VERSION 5.8 ;
BUSBITCHARS "[]" ;
DIVIDERCHAR "/" ;
UNITS
    DATABASE MICRONS 1000 ;
END UNITS

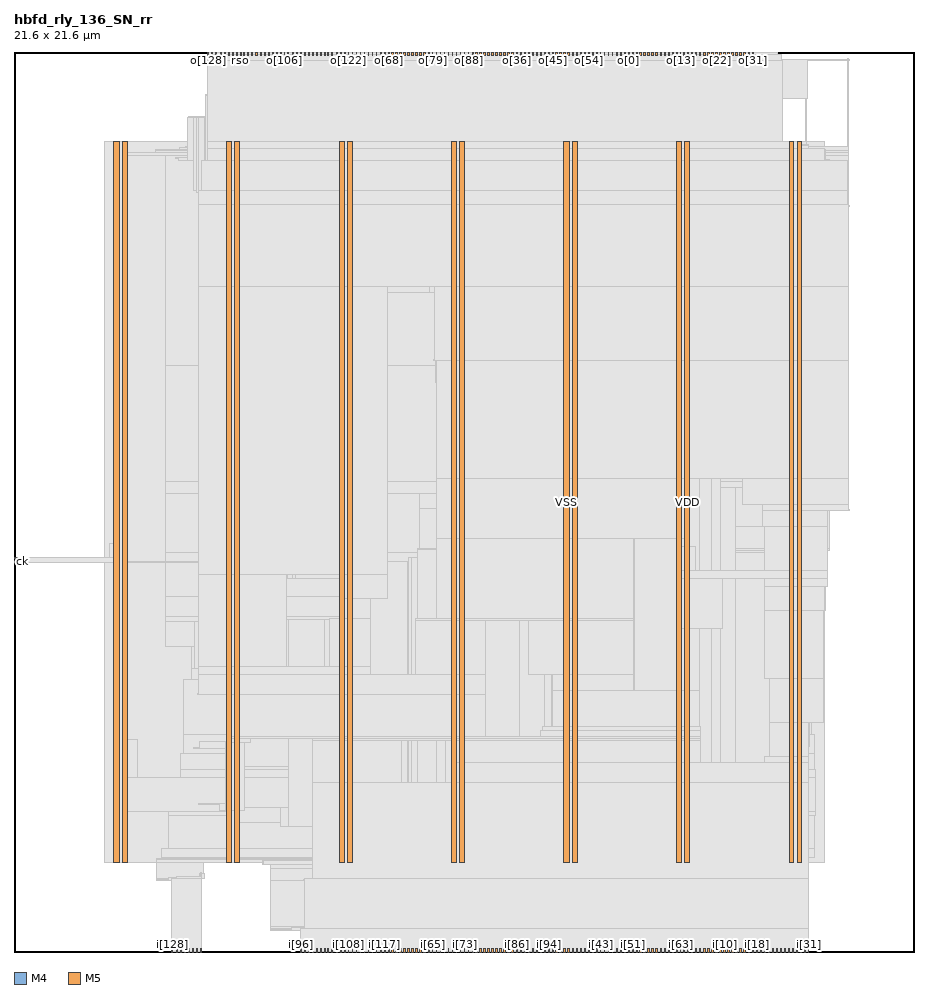
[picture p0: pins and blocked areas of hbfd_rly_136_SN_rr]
MACRO hbfd_rly_136_SN_rr
  FOREIGN hbfd_rly_136_SN_rr 0 0 ;
  CLASS BLOCK ;
  SIZE 21.6 BY 21.6 ;
  PIN ck
    DIRECTION INPUT ;
    USE SIGNAL ;
    PORT
      LAYER M4 ;
        RECT  0 9.36 0.084 9.384 ;
    END
  END ck
  PIN i[0]
    DIRECTION INPUT ;
    USE SIGNAL ;
    PORT
      LAYER M5 ;
        RECT  16.08 0 16.104 0.084 ;
    END
  END i[0]
  PIN i[100]
    DIRECTION INPUT ;
    USE SIGNAL ;
    PORT
      LAYER M5 ;
        RECT  7.248 0 7.272 0.084 ;
    END
  END i[100]
  PIN i[101]
    DIRECTION INPUT ;
    USE SIGNAL ;
    PORT
      LAYER M5 ;
        RECT  7.344 0 7.368 0.084 ;
    END
  END i[101]
  PIN i[102]
    DIRECTION INPUT ;
    USE SIGNAL ;
    PORT
      LAYER M5 ;
        RECT  7.44 0 7.464 0.084 ;
    END
  END i[102]
  PIN i[103]
    DIRECTION INPUT ;
    USE SIGNAL ;
    PORT
      LAYER M5 ;
        RECT  7.536 0 7.56 0.084 ;
    END
  END i[103]
  PIN i[104]
    DIRECTION INPUT ;
    USE SIGNAL ;
    PORT
      LAYER M5 ;
        RECT  7.632 0 7.656 0.084 ;
    END
  END i[104]
  PIN i[105]
    DIRECTION INPUT ;
    USE SIGNAL ;
    PORT
      LAYER M5 ;
        RECT  7.728 0 7.752 0.084 ;
    END
  END i[105]
  PIN i[106]
    DIRECTION INPUT ;
    USE SIGNAL ;
    PORT
      LAYER M5 ;
        RECT  7.824 0 7.848 0.084 ;
    END
  END i[106]
  PIN i[107]
    DIRECTION INPUT ;
    USE SIGNAL ;
    PORT
      LAYER M5 ;
        RECT  7.92 0 7.944 0.084 ;
    END
  END i[107]
  PIN i[108]
    DIRECTION INPUT ;
    USE SIGNAL ;
    PORT
      LAYER M5 ;
        RECT  8.016 0 8.04 0.084 ;
    END
  END i[108]
  PIN i[109]
    DIRECTION INPUT ;
    USE SIGNAL ;
    PORT
      LAYER M5 ;
        RECT  8.112 0 8.136 0.084 ;
    END
  END i[109]
  PIN i[10]
    DIRECTION INPUT ;
    USE SIGNAL ;
    PORT
      LAYER M5 ;
        RECT  17.04 0 17.064 0.084 ;
    END
  END i[10]
  PIN i[110]
    DIRECTION INPUT ;
    USE SIGNAL ;
    PORT
      LAYER M5 ;
        RECT  8.208 0 8.232 0.084 ;
    END
  END i[110]
  PIN i[111]
    DIRECTION INPUT ;
    USE SIGNAL ;
    PORT
      LAYER M5 ;
        RECT  8.304 0 8.328 0.084 ;
    END
  END i[111]
  PIN i[112]
    DIRECTION INPUT ;
    USE SIGNAL ;
    PORT
      LAYER M5 ;
        RECT  8.4 0 8.424 0.084 ;
    END
  END i[112]
  PIN i[113]
    DIRECTION INPUT ;
    USE SIGNAL ;
    PORT
      LAYER M5 ;
        RECT  8.496 0 8.52 0.084 ;
    END
  END i[113]
  PIN i[114]
    DIRECTION INPUT ;
    USE SIGNAL ;
    PORT
      LAYER M5 ;
        RECT  8.592 0 8.616 0.084 ;
    END
  END i[114]
  PIN i[115]
    DIRECTION INPUT ;
    USE SIGNAL ;
    PORT
      LAYER M5 ;
        RECT  8.688 0 8.712 0.084 ;
    END
  END i[115]
  PIN i[116]
    DIRECTION INPUT ;
    USE SIGNAL ;
    PORT
      LAYER M5 ;
        RECT  8.784 0 8.808 0.084 ;
    END
  END i[116]
  PIN i[117]
    DIRECTION INPUT ;
    USE SIGNAL ;
    PORT
      LAYER M5 ;
        RECT  8.88 0 8.904 0.084 ;
    END
  END i[117]
  PIN i[118]
    DIRECTION INPUT ;
    USE SIGNAL ;
    PORT
      LAYER M5 ;
        RECT  8.976 0 9 0.084 ;
    END
  END i[118]
  PIN i[119]
    DIRECTION INPUT ;
    USE SIGNAL ;
    PORT
      LAYER M5 ;
        RECT  9.072 0 9.096 0.084 ;
    END
  END i[119]
  PIN i[11]
    DIRECTION INPUT ;
    USE SIGNAL ;
    PORT
      LAYER M5 ;
        RECT  17.136 0 17.16 0.084 ;
    END
  END i[11]
  PIN i[120]
    DIRECTION INPUT ;
    USE SIGNAL ;
    PORT
      LAYER M5 ;
        RECT  9.168 0 9.192 0.084 ;
    END
  END i[120]
  PIN i[121]
    DIRECTION INPUT ;
    USE SIGNAL ;
    PORT
      LAYER M5 ;
        RECT  9.264 0 9.288 0.084 ;
    END
  END i[121]
  PIN i[122]
    DIRECTION INPUT ;
    USE SIGNAL ;
    PORT
      LAYER M5 ;
        RECT  9.36 0 9.384 0.084 ;
    END
  END i[122]
  PIN i[123]
    DIRECTION INPUT ;
    USE SIGNAL ;
    PORT
      LAYER M5 ;
        RECT  9.456 0 9.48 0.084 ;
    END
  END i[123]
  PIN i[124]
    DIRECTION INPUT ;
    USE SIGNAL ;
    PORT
      LAYER M5 ;
        RECT  9.552 0 9.576 0.084 ;
    END
  END i[124]
  PIN i[125]
    DIRECTION INPUT ;
    USE SIGNAL ;
    PORT
      LAYER M5 ;
        RECT  9.648 0 9.672 0.084 ;
    END
  END i[125]
  PIN i[126]
    DIRECTION INPUT ;
    USE SIGNAL ;
    PORT
      LAYER M5 ;
        RECT  9.744 0 9.768 0.084 ;
    END
  END i[126]
  PIN i[127]
    DIRECTION INPUT ;
    USE SIGNAL ;
    PORT
      LAYER M5 ;
        RECT  9.84 0 9.864 0.084 ;
    END
  END i[127]
  PIN i[128]
    DIRECTION INPUT ;
    USE SIGNAL ;
    PORT
      LAYER M5 ;
        RECT  3.792 0 3.816 0.084 ;
    END
  END i[128]
  PIN i[129]
    DIRECTION INPUT ;
    USE SIGNAL ;
    PORT
      LAYER M5 ;
        RECT  3.888 0 3.912 0.084 ;
    END
  END i[129]
  PIN i[12]
    DIRECTION INPUT ;
    USE SIGNAL ;
    PORT
      LAYER M5 ;
        RECT  17.232 0 17.256 0.084 ;
    END
  END i[12]
  PIN i[130]
    DIRECTION INPUT ;
    USE SIGNAL ;
    PORT
      LAYER M5 ;
        RECT  3.984 0 4.008 0.084 ;
    END
  END i[130]
  PIN i[131]
    DIRECTION INPUT ;
    USE SIGNAL ;
    PORT
      LAYER M5 ;
        RECT  4.08 0 4.104 0.084 ;
    END
  END i[131]
  PIN i[132]
    DIRECTION INPUT ;
    USE SIGNAL ;
    PORT
      LAYER M5 ;
        RECT  4.176 0 4.2 0.084 ;
    END
  END i[132]
  PIN i[133]
    DIRECTION INPUT ;
    USE SIGNAL ;
    PORT
      LAYER M5 ;
        RECT  4.272 0 4.296 0.084 ;
    END
  END i[133]
  PIN i[134]
    DIRECTION INPUT ;
    USE SIGNAL ;
    PORT
      LAYER M5 ;
        RECT  4.368 0 4.392 0.084 ;
    END
  END i[134]
  PIN i[135]
    DIRECTION INPUT ;
    USE SIGNAL ;
    PORT
      LAYER M5 ;
        RECT  4.464 0 4.488 0.084 ;
    END
  END i[135]
  PIN i[13]
    DIRECTION INPUT ;
    USE SIGNAL ;
    PORT
      LAYER M5 ;
        RECT  17.328 0 17.352 0.084 ;
    END
  END i[13]
  PIN i[14]
    DIRECTION INPUT ;
    USE SIGNAL ;
    PORT
      LAYER M5 ;
        RECT  17.424 0 17.448 0.084 ;
    END
  END i[14]
  PIN i[15]
    DIRECTION INPUT ;
    USE SIGNAL ;
    PORT
      LAYER M5 ;
        RECT  17.52 0 17.544 0.084 ;
    END
  END i[15]
  PIN i[16]
    DIRECTION INPUT ;
    USE SIGNAL ;
    PORT
      LAYER M5 ;
        RECT  17.616 0 17.64 0.084 ;
    END
  END i[16]
  PIN i[17]
    DIRECTION INPUT ;
    USE SIGNAL ;
    PORT
      LAYER M5 ;
        RECT  17.712 0 17.736 0.084 ;
    END
  END i[17]
  PIN i[18]
    DIRECTION INPUT ;
    USE SIGNAL ;
    PORT
      LAYER M5 ;
        RECT  17.808 0 17.832 0.084 ;
    END
  END i[18]
  PIN i[19]
    DIRECTION INPUT ;
    USE SIGNAL ;
    PORT
      LAYER M5 ;
        RECT  17.904 0 17.928 0.084 ;
    END
  END i[19]
  PIN i[1]
    DIRECTION INPUT ;
    USE SIGNAL ;
    PORT
      LAYER M5 ;
        RECT  16.176 0 16.2 0.084 ;
    END
  END i[1]
  PIN i[20]
    DIRECTION INPUT ;
    USE SIGNAL ;
    PORT
      LAYER M5 ;
        RECT  18 0 18.024 0.084 ;
    END
  END i[20]
  PIN i[21]
    DIRECTION INPUT ;
    USE SIGNAL ;
    PORT
      LAYER M5 ;
        RECT  18.096 0 18.12 0.084 ;
    END
  END i[21]
  PIN i[22]
    DIRECTION INPUT ;
    USE SIGNAL ;
    PORT
      LAYER M5 ;
        RECT  18.192 0 18.216 0.084 ;
    END
  END i[22]
  PIN i[23]
    DIRECTION INPUT ;
    USE SIGNAL ;
    PORT
      LAYER M5 ;
        RECT  18.288 0 18.312 0.084 ;
    END
  END i[23]
  PIN i[24]
    DIRECTION INPUT ;
    USE SIGNAL ;
    PORT
      LAYER M5 ;
        RECT  18.384 0 18.408 0.084 ;
    END
  END i[24]
  PIN i[25]
    DIRECTION INPUT ;
    USE SIGNAL ;
    PORT
      LAYER M5 ;
        RECT  18.48 0 18.504 0.084 ;
    END
  END i[25]
  PIN i[26]
    DIRECTION INPUT ;
    USE SIGNAL ;
    PORT
      LAYER M5 ;
        RECT  18.576 0 18.6 0.084 ;
    END
  END i[26]
  PIN i[27]
    DIRECTION INPUT ;
    USE SIGNAL ;
    PORT
      LAYER M5 ;
        RECT  18.672 0 18.696 0.084 ;
    END
  END i[27]
  PIN i[28]
    DIRECTION INPUT ;
    USE SIGNAL ;
    PORT
      LAYER M5 ;
        RECT  18.768 0 18.792 0.084 ;
    END
  END i[28]
  PIN i[29]
    DIRECTION INPUT ;
    USE SIGNAL ;
    PORT
      LAYER M5 ;
        RECT  18.864 0 18.888 0.084 ;
    END
  END i[29]
  PIN i[2]
    DIRECTION INPUT ;
    USE SIGNAL ;
    PORT
      LAYER M5 ;
        RECT  16.272 0 16.296 0.084 ;
    END
  END i[2]
  PIN i[30]
    DIRECTION INPUT ;
    USE SIGNAL ;
    PORT
      LAYER M5 ;
        RECT  18.96 0 18.984 0.084 ;
    END
  END i[30]
  PIN i[31]
    DIRECTION INPUT ;
    USE SIGNAL ;
    PORT
      LAYER M5 ;
        RECT  19.056 0 19.08 0.084 ;
    END
  END i[31]
  PIN i[32]
    DIRECTION INPUT ;
    USE SIGNAL ;
    PORT
      LAYER M5 ;
        RECT  13.008 0 13.032 0.084 ;
    END
  END i[32]
  PIN i[33]
    DIRECTION INPUT ;
    USE SIGNAL ;
    PORT
      LAYER M5 ;
        RECT  13.104 0 13.128 0.084 ;
    END
  END i[33]
  PIN i[34]
    DIRECTION INPUT ;
    USE SIGNAL ;
    PORT
      LAYER M5 ;
        RECT  13.2 0 13.224 0.084 ;
    END
  END i[34]
  PIN i[35]
    DIRECTION INPUT ;
    USE SIGNAL ;
    PORT
      LAYER M5 ;
        RECT  13.296 0 13.32 0.084 ;
    END
  END i[35]
  PIN i[36]
    DIRECTION INPUT ;
    USE SIGNAL ;
    PORT
      LAYER M5 ;
        RECT  13.392 0 13.416 0.084 ;
    END
  END i[36]
  PIN i[37]
    DIRECTION INPUT ;
    USE SIGNAL ;
    PORT
      LAYER M5 ;
        RECT  13.488 0 13.512 0.084 ;
    END
  END i[37]
  PIN i[38]
    DIRECTION INPUT ;
    USE SIGNAL ;
    PORT
      LAYER M5 ;
        RECT  13.584 0 13.608 0.084 ;
    END
  END i[38]
  PIN i[39]
    DIRECTION INPUT ;
    USE SIGNAL ;
    PORT
      LAYER M5 ;
        RECT  13.68 0 13.704 0.084 ;
    END
  END i[39]
  PIN i[3]
    DIRECTION INPUT ;
    USE SIGNAL ;
    PORT
      LAYER M5 ;
        RECT  16.368 0 16.392 0.084 ;
    END
  END i[3]
  PIN i[40]
    DIRECTION INPUT ;
    USE SIGNAL ;
    PORT
      LAYER M5 ;
        RECT  13.776 0 13.8 0.084 ;
    END
  END i[40]
  PIN i[41]
    DIRECTION INPUT ;
    USE SIGNAL ;
    PORT
      LAYER M5 ;
        RECT  13.872 0 13.896 0.084 ;
    END
  END i[41]
  PIN i[42]
    DIRECTION INPUT ;
    USE SIGNAL ;
    PORT
      LAYER M5 ;
        RECT  13.968 0 13.992 0.084 ;
    END
  END i[42]
  PIN i[43]
    DIRECTION INPUT ;
    USE SIGNAL ;
    PORT
      LAYER M5 ;
        RECT  14.064 0 14.088 0.084 ;
    END
  END i[43]
  PIN i[44]
    DIRECTION INPUT ;
    USE SIGNAL ;
    PORT
      LAYER M5 ;
        RECT  14.16 0 14.184 0.084 ;
    END
  END i[44]
  PIN i[45]
    DIRECTION INPUT ;
    USE SIGNAL ;
    PORT
      LAYER M5 ;
        RECT  14.256 0 14.28 0.084 ;
    END
  END i[45]
  PIN i[46]
    DIRECTION INPUT ;
    USE SIGNAL ;
    PORT
      LAYER M5 ;
        RECT  14.352 0 14.376 0.084 ;
    END
  END i[46]
  PIN i[47]
    DIRECTION INPUT ;
    USE SIGNAL ;
    PORT
      LAYER M5 ;
        RECT  14.448 0 14.472 0.084 ;
    END
  END i[47]
  PIN i[48]
    DIRECTION INPUT ;
    USE SIGNAL ;
    PORT
      LAYER M5 ;
        RECT  14.544 0 14.568 0.084 ;
    END
  END i[48]
  PIN i[49]
    DIRECTION INPUT ;
    USE SIGNAL ;
    PORT
      LAYER M5 ;
        RECT  14.64 0 14.664 0.084 ;
    END
  END i[49]
  PIN i[4]
    DIRECTION INPUT ;
    USE SIGNAL ;
    PORT
      LAYER M5 ;
        RECT  16.464 0 16.488 0.084 ;
    END
  END i[4]
  PIN i[50]
    DIRECTION INPUT ;
    USE SIGNAL ;
    PORT
      LAYER M5 ;
        RECT  14.736 0 14.76 0.084 ;
    END
  END i[50]
  PIN i[51]
    DIRECTION INPUT ;
    USE SIGNAL ;
    PORT
      LAYER M5 ;
        RECT  14.832 0 14.856 0.084 ;
    END
  END i[51]
  PIN i[52]
    DIRECTION INPUT ;
    USE SIGNAL ;
    PORT
      LAYER M5 ;
        RECT  14.928 0 14.952 0.084 ;
    END
  END i[52]
  PIN i[53]
    DIRECTION INPUT ;
    USE SIGNAL ;
    PORT
      LAYER M5 ;
        RECT  15.024 0 15.048 0.084 ;
    END
  END i[53]
  PIN i[54]
    DIRECTION INPUT ;
    USE SIGNAL ;
    PORT
      LAYER M5 ;
        RECT  15.12 0 15.144 0.084 ;
    END
  END i[54]
  PIN i[55]
    DIRECTION INPUT ;
    USE SIGNAL ;
    PORT
      LAYER M5 ;
        RECT  15.216 0 15.24 0.084 ;
    END
  END i[55]
  PIN i[56]
    DIRECTION INPUT ;
    USE SIGNAL ;
    PORT
      LAYER M5 ;
        RECT  15.312 0 15.336 0.084 ;
    END
  END i[56]
  PIN i[57]
    DIRECTION INPUT ;
    USE SIGNAL ;
    PORT
      LAYER M5 ;
        RECT  15.408 0 15.432 0.084 ;
    END
  END i[57]
  PIN i[58]
    DIRECTION INPUT ;
    USE SIGNAL ;
    PORT
      LAYER M5 ;
        RECT  15.504 0 15.528 0.084 ;
    END
  END i[58]
  PIN i[59]
    DIRECTION INPUT ;
    USE SIGNAL ;
    PORT
      LAYER M5 ;
        RECT  15.6 0 15.624 0.084 ;
    END
  END i[59]
  PIN i[5]
    DIRECTION INPUT ;
    USE SIGNAL ;
    PORT
      LAYER M5 ;
        RECT  16.56 0 16.584 0.084 ;
    END
  END i[5]
  PIN i[60]
    DIRECTION INPUT ;
    USE SIGNAL ;
    PORT
      LAYER M5 ;
        RECT  15.696 0 15.72 0.084 ;
    END
  END i[60]
  PIN i[61]
    DIRECTION INPUT ;
    USE SIGNAL ;
    PORT
      LAYER M5 ;
        RECT  15.792 0 15.816 0.084 ;
    END
  END i[61]
  PIN i[62]
    DIRECTION INPUT ;
    USE SIGNAL ;
    PORT
      LAYER M5 ;
        RECT  15.888 0 15.912 0.084 ;
    END
  END i[62]
  PIN i[63]
    DIRECTION INPUT ;
    USE SIGNAL ;
    PORT
      LAYER M5 ;
        RECT  15.984 0 16.008 0.084 ;
    END
  END i[63]
  PIN i[64]
    DIRECTION INPUT ;
    USE SIGNAL ;
    PORT
      LAYER M5 ;
        RECT  9.936 0 9.96 0.084 ;
    END
  END i[64]
  PIN i[65]
    DIRECTION INPUT ;
    USE SIGNAL ;
    PORT
      LAYER M5 ;
        RECT  10.032 0 10.056 0.084 ;
    END
  END i[65]
  PIN i[66]
    DIRECTION INPUT ;
    USE SIGNAL ;
    PORT
      LAYER M5 ;
        RECT  10.128 0 10.152 0.084 ;
    END
  END i[66]
  PIN i[67]
    DIRECTION INPUT ;
    USE SIGNAL ;
    PORT
      LAYER M5 ;
        RECT  10.224 0 10.248 0.084 ;
    END
  END i[67]
  PIN i[68]
    DIRECTION INPUT ;
    USE SIGNAL ;
    PORT
      LAYER M5 ;
        RECT  10.32 0 10.344 0.084 ;
    END
  END i[68]
  PIN i[69]
    DIRECTION INPUT ;
    USE SIGNAL ;
    PORT
      LAYER M5 ;
        RECT  10.416 0 10.44 0.084 ;
    END
  END i[69]
  PIN i[6]
    DIRECTION INPUT ;
    USE SIGNAL ;
    PORT
      LAYER M5 ;
        RECT  16.656 0 16.68 0.084 ;
    END
  END i[6]
  PIN i[70]
    DIRECTION INPUT ;
    USE SIGNAL ;
    PORT
      LAYER M5 ;
        RECT  10.512 0 10.536 0.084 ;
    END
  END i[70]
  PIN i[71]
    DIRECTION INPUT ;
    USE SIGNAL ;
    PORT
      LAYER M5 ;
        RECT  10.608 0 10.632 0.084 ;
    END
  END i[71]
  PIN i[72]
    DIRECTION INPUT ;
    USE SIGNAL ;
    PORT
      LAYER M5 ;
        RECT  10.704 0 10.728 0.084 ;
    END
  END i[72]
  PIN i[73]
    DIRECTION INPUT ;
    USE SIGNAL ;
    PORT
      LAYER M5 ;
        RECT  10.8 0 10.824 0.084 ;
    END
  END i[73]
  PIN i[74]
    DIRECTION INPUT ;
    USE SIGNAL ;
    PORT
      LAYER M5 ;
        RECT  10.896 0 10.92 0.084 ;
    END
  END i[74]
  PIN i[75]
    DIRECTION INPUT ;
    USE SIGNAL ;
    PORT
      LAYER M5 ;
        RECT  10.992 0 11.016 0.084 ;
    END
  END i[75]
  PIN i[76]
    DIRECTION INPUT ;
    USE SIGNAL ;
    PORT
      LAYER M5 ;
        RECT  11.088 0 11.112 0.084 ;
    END
  END i[76]
  PIN i[77]
    DIRECTION INPUT ;
    USE SIGNAL ;
    PORT
      LAYER M5 ;
        RECT  11.184 0 11.208 0.084 ;
    END
  END i[77]
  PIN i[78]
    DIRECTION INPUT ;
    USE SIGNAL ;
    PORT
      LAYER M5 ;
        RECT  11.28 0 11.304 0.084 ;
    END
  END i[78]
  PIN i[79]
    DIRECTION INPUT ;
    USE SIGNAL ;
    PORT
      LAYER M5 ;
        RECT  11.376 0 11.4 0.084 ;
    END
  END i[79]
  PIN i[7]
    DIRECTION INPUT ;
    USE SIGNAL ;
    PORT
      LAYER M5 ;
        RECT  16.752 0 16.776 0.084 ;
    END
  END i[7]
  PIN i[80]
    DIRECTION INPUT ;
    USE SIGNAL ;
    PORT
      LAYER M5 ;
        RECT  11.472 0 11.496 0.084 ;
    END
  END i[80]
  PIN i[81]
    DIRECTION INPUT ;
    USE SIGNAL ;
    PORT
      LAYER M5 ;
        RECT  11.568 0 11.592 0.084 ;
    END
  END i[81]
  PIN i[82]
    DIRECTION INPUT ;
    USE SIGNAL ;
    PORT
      LAYER M5 ;
        RECT  11.664 0 11.688 0.084 ;
    END
  END i[82]
  PIN i[83]
    DIRECTION INPUT ;
    USE SIGNAL ;
    PORT
      LAYER M5 ;
        RECT  11.76 0 11.784 0.084 ;
    END
  END i[83]
  PIN i[84]
    DIRECTION INPUT ;
    USE SIGNAL ;
    PORT
      LAYER M5 ;
        RECT  11.856 0 11.88 0.084 ;
    END
  END i[84]
  PIN i[85]
    DIRECTION INPUT ;
    USE SIGNAL ;
    PORT
      LAYER M5 ;
        RECT  11.952 0 11.976 0.084 ;
    END
  END i[85]
  PIN i[86]
    DIRECTION INPUT ;
    USE SIGNAL ;
    PORT
      LAYER M5 ;
        RECT  12.048 0 12.072 0.084 ;
    END
  END i[86]
  PIN i[87]
    DIRECTION INPUT ;
    USE SIGNAL ;
    PORT
      LAYER M5 ;
        RECT  12.144 0 12.168 0.084 ;
    END
  END i[87]
  PIN i[88]
    DIRECTION INPUT ;
    USE SIGNAL ;
    PORT
      LAYER M5 ;
        RECT  12.24 0 12.264 0.084 ;
    END
  END i[88]
  PIN i[89]
    DIRECTION INPUT ;
    USE SIGNAL ;
    PORT
      LAYER M5 ;
        RECT  12.336 0 12.36 0.084 ;
    END
  END i[89]
  PIN i[8]
    DIRECTION INPUT ;
    USE SIGNAL ;
    PORT
      LAYER M5 ;
        RECT  16.848 0 16.872 0.084 ;
    END
  END i[8]
  PIN i[90]
    DIRECTION INPUT ;
    USE SIGNAL ;
    PORT
      LAYER M5 ;
        RECT  12.432 0 12.456 0.084 ;
    END
  END i[90]
  PIN i[91]
    DIRECTION INPUT ;
    USE SIGNAL ;
    PORT
      LAYER M5 ;
        RECT  12.528 0 12.552 0.084 ;
    END
  END i[91]
  PIN i[92]
    DIRECTION INPUT ;
    USE SIGNAL ;
    PORT
      LAYER M5 ;
        RECT  12.624 0 12.648 0.084 ;
    END
  END i[92]
  PIN i[93]
    DIRECTION INPUT ;
    USE SIGNAL ;
    PORT
      LAYER M5 ;
        RECT  12.72 0 12.744 0.084 ;
    END
  END i[93]
  PIN i[94]
    DIRECTION INPUT ;
    USE SIGNAL ;
    PORT
      LAYER M5 ;
        RECT  12.816 0 12.84 0.084 ;
    END
  END i[94]
  PIN i[95]
    DIRECTION INPUT ;
    USE SIGNAL ;
    PORT
      LAYER M5 ;
        RECT  12.912 0 12.936 0.084 ;
    END
  END i[95]
  PIN i[96]
    DIRECTION INPUT ;
    USE SIGNAL ;
    PORT
      LAYER M5 ;
        RECT  6.864 0 6.888 0.084 ;
    END
  END i[96]
  PIN i[97]
    DIRECTION INPUT ;
    USE SIGNAL ;
    PORT
      LAYER M5 ;
        RECT  6.96 0 6.984 0.084 ;
    END
  END i[97]
  PIN i[98]
    DIRECTION INPUT ;
    USE SIGNAL ;
    PORT
      LAYER M5 ;
        RECT  7.056 0 7.08 0.084 ;
    END
  END i[98]
  PIN i[99]
    DIRECTION INPUT ;
    USE SIGNAL ;
    PORT
      LAYER M5 ;
        RECT  7.152 0 7.176 0.084 ;
    END
  END i[99]
  PIN i[9]
    DIRECTION INPUT ;
    USE SIGNAL ;
    PORT
      LAYER M5 ;
        RECT  16.944 0 16.968 0.084 ;
    END
  END i[9]
  PIN o[0]
    DIRECTION OUTPUT ;
    USE SIGNAL ;
    PORT
      LAYER M5 ;
        RECT  14.736 21.516 14.76 21.6 ;
    END
  END o[0]
  PIN o[100]
    DIRECTION OUTPUT ;
    USE SIGNAL ;
    PORT
      LAYER M5 ;
        RECT  5.904 21.516 5.928 21.6 ;
    END
  END o[100]
  PIN o[101]
    DIRECTION OUTPUT ;
    USE SIGNAL ;
    PORT
      LAYER M5 ;
        RECT  6 21.516 6.024 21.6 ;
    END
  END o[101]
  PIN o[102]
    DIRECTION OUTPUT ;
    USE SIGNAL ;
    PORT
      LAYER M5 ;
        RECT  6.096 21.516 6.12 21.6 ;
    END
  END o[102]
  PIN o[103]
    DIRECTION OUTPUT ;
    USE SIGNAL ;
    PORT
      LAYER M5 ;
        RECT  6.192 21.516 6.216 21.6 ;
    END
  END o[103]
  PIN o[104]
    DIRECTION OUTPUT ;
    USE SIGNAL ;
    PORT
      LAYER M5 ;
        RECT  6.288 21.516 6.312 21.6 ;
    END
  END o[104]
  PIN o[105]
    DIRECTION OUTPUT ;
    USE SIGNAL ;
    PORT
      LAYER M5 ;
        RECT  6.384 21.516 6.408 21.6 ;
    END
  END o[105]
  PIN o[106]
    DIRECTION OUTPUT ;
    USE SIGNAL ;
    PORT
      LAYER M5 ;
        RECT  6.48 21.516 6.504 21.6 ;
    END
  END o[106]
  PIN o[107]
    DIRECTION OUTPUT ;
    USE SIGNAL ;
    PORT
      LAYER M5 ;
        RECT  6.576 21.516 6.6 21.6 ;
    END
  END o[107]
  PIN o[108]
    DIRECTION OUTPUT ;
    USE SIGNAL ;
    PORT
      LAYER M5 ;
        RECT  6.672 21.516 6.696 21.6 ;
    END
  END o[108]
  PIN o[109]
    DIRECTION OUTPUT ;
    USE SIGNAL ;
    PORT
      LAYER M5 ;
        RECT  6.768 21.516 6.792 21.6 ;
    END
  END o[109]
  PIN o[10]
    DIRECTION OUTPUT ;
    USE SIGNAL ;
    PORT
      LAYER M5 ;
        RECT  15.696 21.516 15.72 21.6 ;
    END
  END o[10]
  PIN o[110]
    DIRECTION OUTPUT ;
    USE SIGNAL ;
    PORT
      LAYER M5 ;
        RECT  6.864 21.516 6.888 21.6 ;
    END
  END o[110]
  PIN o[111]
    DIRECTION OUTPUT ;
    USE SIGNAL ;
    PORT
      LAYER M5 ;
        RECT  6.96 21.516 6.984 21.6 ;
    END
  END o[111]
  PIN o[112]
    DIRECTION OUTPUT ;
    USE SIGNAL ;
    PORT
      LAYER M5 ;
        RECT  7.056 21.516 7.08 21.6 ;
    END
  END o[112]
  PIN o[113]
    DIRECTION OUTPUT ;
    USE SIGNAL ;
    PORT
      LAYER M5 ;
        RECT  7.152 21.516 7.176 21.6 ;
    END
  END o[113]
  PIN o[114]
    DIRECTION OUTPUT ;
    USE SIGNAL ;
    PORT
      LAYER M5 ;
        RECT  7.248 21.516 7.272 21.6 ;
    END
  END o[114]
  PIN o[115]
    DIRECTION OUTPUT ;
    USE SIGNAL ;
    PORT
      LAYER M5 ;
        RECT  7.344 21.516 7.368 21.6 ;
    END
  END o[115]
  PIN o[116]
    DIRECTION OUTPUT ;
    USE SIGNAL ;
    PORT
      LAYER M5 ;
        RECT  7.44 21.516 7.464 21.6 ;
    END
  END o[116]
  PIN o[117]
    DIRECTION OUTPUT ;
    USE SIGNAL ;
    PORT
      LAYER M5 ;
        RECT  7.536 21.516 7.56 21.6 ;
    END
  END o[117]
  PIN o[118]
    DIRECTION OUTPUT ;
    USE SIGNAL ;
    PORT
      LAYER M5 ;
        RECT  7.632 21.516 7.656 21.6 ;
    END
  END o[118]
  PIN o[119]
    DIRECTION OUTPUT ;
    USE SIGNAL ;
    PORT
      LAYER M5 ;
        RECT  7.728 21.516 7.752 21.6 ;
    END
  END o[119]
  PIN o[11]
    DIRECTION OUTPUT ;
    USE SIGNAL ;
    PORT
      LAYER M5 ;
        RECT  15.792 21.516 15.816 21.6 ;
    END
  END o[11]
  PIN o[120]
    DIRECTION OUTPUT ;
    USE SIGNAL ;
    PORT
      LAYER M5 ;
        RECT  7.824 21.516 7.848 21.6 ;
    END
  END o[120]
  PIN o[121]
    DIRECTION OUTPUT ;
    USE SIGNAL ;
    PORT
      LAYER M5 ;
        RECT  7.92 21.516 7.944 21.6 ;
    END
  END o[121]
  PIN o[122]
    DIRECTION OUTPUT ;
    USE SIGNAL ;
    PORT
      LAYER M5 ;
        RECT  8.016 21.516 8.04 21.6 ;
    END
  END o[122]
  PIN o[123]
    DIRECTION OUTPUT ;
    USE SIGNAL ;
    PORT
      LAYER M5 ;
        RECT  8.112 21.516 8.136 21.6 ;
    END
  END o[123]
  PIN o[124]
    DIRECTION OUTPUT ;
    USE SIGNAL ;
    PORT
      LAYER M5 ;
        RECT  8.208 21.516 8.232 21.6 ;
    END
  END o[124]
  PIN o[125]
    DIRECTION OUTPUT ;
    USE SIGNAL ;
    PORT
      LAYER M5 ;
        RECT  8.304 21.516 8.328 21.6 ;
    END
  END o[125]
  PIN o[126]
    DIRECTION OUTPUT ;
    USE SIGNAL ;
    PORT
      LAYER M5 ;
        RECT  8.4 21.516 8.424 21.6 ;
    END
  END o[126]
  PIN o[127]
    DIRECTION OUTPUT ;
    USE SIGNAL ;
    PORT
      LAYER M5 ;
        RECT  8.496 21.516 8.52 21.6 ;
    END
  END o[127]
  PIN o[128]
    DIRECTION OUTPUT ;
    USE SIGNAL ;
    PORT
      LAYER M5 ;
        RECT  4.656 21.516 4.68 21.6 ;
    END
  END o[128]
  PIN o[129]
    DIRECTION OUTPUT ;
    USE SIGNAL ;
    PORT
      LAYER M5 ;
        RECT  4.752 21.516 4.776 21.6 ;
    END
  END o[129]
  PIN o[12]
    DIRECTION OUTPUT ;
    USE SIGNAL ;
    PORT
      LAYER M5 ;
        RECT  15.888 21.516 15.912 21.6 ;
    END
  END o[12]
  PIN o[130]
    DIRECTION OUTPUT ;
    USE SIGNAL ;
    PORT
      LAYER M5 ;
        RECT  4.848 21.516 4.872 21.6 ;
    END
  END o[130]
  PIN o[131]
    DIRECTION OUTPUT ;
    USE SIGNAL ;
    PORT
      LAYER M5 ;
        RECT  4.944 21.516 4.968 21.6 ;
    END
  END o[131]
  PIN o[132]
    DIRECTION OUTPUT ;
    USE SIGNAL ;
    PORT
      LAYER M5 ;
        RECT  5.04 21.516 5.064 21.6 ;
    END
  END o[132]
  PIN o[133]
    DIRECTION OUTPUT ;
    USE SIGNAL ;
    PORT
      LAYER M5 ;
        RECT  5.136 21.516 5.16 21.6 ;
    END
  END o[133]
  PIN o[134]
    DIRECTION OUTPUT ;
    USE SIGNAL ;
    PORT
      LAYER M5 ;
        RECT  5.232 21.516 5.256 21.6 ;
    END
  END o[134]
  PIN o[135]
    DIRECTION OUTPUT ;
    USE SIGNAL ;
    PORT
      LAYER M5 ;
        RECT  5.328 21.516 5.352 21.6 ;
    END
  END o[135]
  PIN o[13]
    DIRECTION OUTPUT ;
    USE SIGNAL ;
    PORT
      LAYER M5 ;
        RECT  15.984 21.516 16.008 21.6 ;
    END
  END o[13]
  PIN o[14]
    DIRECTION OUTPUT ;
    USE SIGNAL ;
    PORT
      LAYER M5 ;
        RECT  16.08 21.516 16.104 21.6 ;
    END
  END o[14]
  PIN o[15]
    DIRECTION OUTPUT ;
    USE SIGNAL ;
    PORT
      LAYER M5 ;
        RECT  16.176 21.516 16.2 21.6 ;
    END
  END o[15]
  PIN o[16]
    DIRECTION OUTPUT ;
    USE SIGNAL ;
    PORT
      LAYER M5 ;
        RECT  16.272 21.516 16.296 21.6 ;
    END
  END o[16]
  PIN o[17]
    DIRECTION OUTPUT ;
    USE SIGNAL ;
    PORT
      LAYER M5 ;
        RECT  16.368 21.516 16.392 21.6 ;
    END
  END o[17]
  PIN o[18]
    DIRECTION OUTPUT ;
    USE SIGNAL ;
    PORT
      LAYER M5 ;
        RECT  16.464 21.516 16.488 21.6 ;
    END
  END o[18]
  PIN o[19]
    DIRECTION OUTPUT ;
    USE SIGNAL ;
    PORT
      LAYER M5 ;
        RECT  16.56 21.516 16.584 21.6 ;
    END
  END o[19]
  PIN o[1]
    DIRECTION OUTPUT ;
    USE SIGNAL ;
    PORT
      LAYER M5 ;
        RECT  14.832 21.516 14.856 21.6 ;
    END
  END o[1]
  PIN o[20]
    DIRECTION OUTPUT ;
    USE SIGNAL ;
    PORT
      LAYER M5 ;
        RECT  16.656 21.516 16.68 21.6 ;
    END
  END o[20]
  PIN o[21]
    DIRECTION OUTPUT ;
    USE SIGNAL ;
    PORT
      LAYER M5 ;
        RECT  16.752 21.516 16.776 21.6 ;
    END
  END o[21]
  PIN o[22]
    DIRECTION OUTPUT ;
    USE SIGNAL ;
    PORT
      LAYER M5 ;
        RECT  16.848 21.516 16.872 21.6 ;
    END
  END o[22]
  PIN o[23]
    DIRECTION OUTPUT ;
    USE SIGNAL ;
    PORT
      LAYER M5 ;
        RECT  16.944 21.516 16.968 21.6 ;
    END
  END o[23]
  PIN o[24]
    DIRECTION OUTPUT ;
    USE SIGNAL ;
    PORT
      LAYER M5 ;
        RECT  17.04 21.516 17.064 21.6 ;
    END
  END o[24]
  PIN o[25]
    DIRECTION OUTPUT ;
    USE SIGNAL ;
    PORT
      LAYER M5 ;
        RECT  17.136 21.516 17.16 21.6 ;
    END
  END o[25]
  PIN o[26]
    DIRECTION OUTPUT ;
    USE SIGNAL ;
    PORT
      LAYER M5 ;
        RECT  17.232 21.516 17.256 21.6 ;
    END
  END o[26]
  PIN o[27]
    DIRECTION OUTPUT ;
    USE SIGNAL ;
    PORT
      LAYER M5 ;
        RECT  17.328 21.516 17.352 21.6 ;
    END
  END o[27]
  PIN o[28]
    DIRECTION OUTPUT ;
    USE SIGNAL ;
    PORT
      LAYER M5 ;
        RECT  17.424 21.516 17.448 21.6 ;
    END
  END o[28]
  PIN o[29]
    DIRECTION OUTPUT ;
    USE SIGNAL ;
    PORT
      LAYER M5 ;
        RECT  17.52 21.516 17.544 21.6 ;
    END
  END o[29]
  PIN o[2]
    DIRECTION OUTPUT ;
    USE SIGNAL ;
    PORT
      LAYER M5 ;
        RECT  14.928 21.516 14.952 21.6 ;
    END
  END o[2]
  PIN o[30]
    DIRECTION OUTPUT ;
    USE SIGNAL ;
    PORT
      LAYER M5 ;
        RECT  17.616 21.516 17.64 21.6 ;
    END
  END o[30]
  PIN o[31]
    DIRECTION OUTPUT ;
    USE SIGNAL ;
    PORT
      LAYER M5 ;
        RECT  17.712 21.516 17.736 21.6 ;
    END
  END o[31]
  PIN o[32]
    DIRECTION OUTPUT ;
    USE SIGNAL ;
    PORT
      LAYER M5 ;
        RECT  11.664 21.516 11.688 21.6 ;
    END
  END o[32]
  PIN o[33]
    DIRECTION OUTPUT ;
    USE SIGNAL ;
    PORT
      LAYER M5 ;
        RECT  11.76 21.516 11.784 21.6 ;
    END
  END o[33]
  PIN o[34]
    DIRECTION OUTPUT ;
    USE SIGNAL ;
    PORT
      LAYER M5 ;
        RECT  11.856 21.516 11.88 21.6 ;
    END
  END o[34]
  PIN o[35]
    DIRECTION OUTPUT ;
    USE SIGNAL ;
    PORT
      LAYER M5 ;
        RECT  11.952 21.516 11.976 21.6 ;
    END
  END o[35]
  PIN o[36]
    DIRECTION OUTPUT ;
    USE SIGNAL ;
    PORT
      LAYER M5 ;
        RECT  12.048 21.516 12.072 21.6 ;
    END
  END o[36]
  PIN o[37]
    DIRECTION OUTPUT ;
    USE SIGNAL ;
    PORT
      LAYER M5 ;
        RECT  12.144 21.516 12.168 21.6 ;
    END
  END o[37]
  PIN o[38]
    DIRECTION OUTPUT ;
    USE SIGNAL ;
    PORT
      LAYER M5 ;
        RECT  12.24 21.516 12.264 21.6 ;
    END
  END o[38]
  PIN o[39]
    DIRECTION OUTPUT ;
    USE SIGNAL ;
    PORT
      LAYER M5 ;
        RECT  12.336 21.516 12.36 21.6 ;
    END
  END o[39]
  PIN o[3]
    DIRECTION OUTPUT ;
    USE SIGNAL ;
    PORT
      LAYER M5 ;
        RECT  15.024 21.516 15.048 21.6 ;
    END
  END o[3]
  PIN o[40]
    DIRECTION OUTPUT ;
    USE SIGNAL ;
    PORT
      LAYER M5 ;
        RECT  12.432 21.516 12.456 21.6 ;
    END
  END o[40]
  PIN o[41]
    DIRECTION OUTPUT ;
    USE SIGNAL ;
    PORT
      LAYER M5 ;
        RECT  12.528 21.516 12.552 21.6 ;
    END
  END o[41]
  PIN o[42]
    DIRECTION OUTPUT ;
    USE SIGNAL ;
    PORT
      LAYER M5 ;
        RECT  12.624 21.516 12.648 21.6 ;
    END
  END o[42]
  PIN o[43]
    DIRECTION OUTPUT ;
    USE SIGNAL ;
    PORT
      LAYER M5 ;
        RECT  12.72 21.516 12.744 21.6 ;
    END
  END o[43]
  PIN o[44]
    DIRECTION OUTPUT ;
    USE SIGNAL ;
    PORT
      LAYER M5 ;
        RECT  12.816 21.516 12.84 21.6 ;
    END
  END o[44]
  PIN o[45]
    DIRECTION OUTPUT ;
    USE SIGNAL ;
    PORT
      LAYER M5 ;
        RECT  12.912 21.516 12.936 21.6 ;
    END
  END o[45]
  PIN o[46]
    DIRECTION OUTPUT ;
    USE SIGNAL ;
    PORT
      LAYER M5 ;
        RECT  13.008 21.516 13.032 21.6 ;
    END
  END o[46]
  PIN o[47]
    DIRECTION OUTPUT ;
    USE SIGNAL ;
    PORT
      LAYER M5 ;
        RECT  13.104 21.516 13.128 21.6 ;
    END
  END o[47]
  PIN o[48]
    DIRECTION OUTPUT ;
    USE SIGNAL ;
    PORT
      LAYER M5 ;
        RECT  13.2 21.516 13.224 21.6 ;
    END
  END o[48]
  PIN o[49]
    DIRECTION OUTPUT ;
    USE SIGNAL ;
    PORT
      LAYER M5 ;
        RECT  13.296 21.516 13.32 21.6 ;
    END
  END o[49]
  PIN o[4]
    DIRECTION OUTPUT ;
    USE SIGNAL ;
    PORT
      LAYER M5 ;
        RECT  15.12 21.516 15.144 21.6 ;
    END
  END o[4]
  PIN o[50]
    DIRECTION OUTPUT ;
    USE SIGNAL ;
    PORT
      LAYER M5 ;
        RECT  13.392 21.516 13.416 21.6 ;
    END
  END o[50]
  PIN o[51]
    DIRECTION OUTPUT ;
    USE SIGNAL ;
    PORT
      LAYER M5 ;
        RECT  13.488 21.516 13.512 21.6 ;
    END
  END o[51]
  PIN o[52]
    DIRECTION OUTPUT ;
    USE SIGNAL ;
    PORT
      LAYER M5 ;
        RECT  13.584 21.516 13.608 21.6 ;
    END
  END o[52]
  PIN o[53]
    DIRECTION OUTPUT ;
    USE SIGNAL ;
    PORT
      LAYER M5 ;
        RECT  13.68 21.516 13.704 21.6 ;
    END
  END o[53]
  PIN o[54]
    DIRECTION OUTPUT ;
    USE SIGNAL ;
    PORT
      LAYER M5 ;
        RECT  13.776 21.516 13.8 21.6 ;
    END
  END o[54]
  PIN o[55]
    DIRECTION OUTPUT ;
    USE SIGNAL ;
    PORT
      LAYER M5 ;
        RECT  13.872 21.516 13.896 21.6 ;
    END
  END o[55]
  PIN o[56]
    DIRECTION OUTPUT ;
    USE SIGNAL ;
    PORT
      LAYER M5 ;
        RECT  13.968 21.516 13.992 21.6 ;
    END
  END o[56]
  PIN o[57]
    DIRECTION OUTPUT ;
    USE SIGNAL ;
    PORT
      LAYER M5 ;
        RECT  14.064 21.516 14.088 21.6 ;
    END
  END o[57]
  PIN o[58]
    DIRECTION OUTPUT ;
    USE SIGNAL ;
    PORT
      LAYER M5 ;
        RECT  14.16 21.516 14.184 21.6 ;
    END
  END o[58]
  PIN o[59]
    DIRECTION OUTPUT ;
    USE SIGNAL ;
    PORT
      LAYER M5 ;
        RECT  14.256 21.516 14.28 21.6 ;
    END
  END o[59]
  PIN o[5]
    DIRECTION OUTPUT ;
    USE SIGNAL ;
    PORT
      LAYER M5 ;
        RECT  15.216 21.516 15.24 21.6 ;
    END
  END o[5]
  PIN o[60]
    DIRECTION OUTPUT ;
    USE SIGNAL ;
    PORT
      LAYER M5 ;
        RECT  14.352 21.516 14.376 21.6 ;
    END
  END o[60]
  PIN o[61]
    DIRECTION OUTPUT ;
    USE SIGNAL ;
    PORT
      LAYER M5 ;
        RECT  14.448 21.516 14.472 21.6 ;
    END
  END o[61]
  PIN o[62]
    DIRECTION OUTPUT ;
    USE SIGNAL ;
    PORT
      LAYER M5 ;
        RECT  14.544 21.516 14.568 21.6 ;
    END
  END o[62]
  PIN o[63]
    DIRECTION OUTPUT ;
    USE SIGNAL ;
    PORT
      LAYER M5 ;
        RECT  14.64 21.516 14.664 21.6 ;
    END
  END o[63]
  PIN o[64]
    DIRECTION OUTPUT ;
    USE SIGNAL ;
    PORT
      LAYER M5 ;
        RECT  8.592 21.516 8.616 21.6 ;
    END
  END o[64]
  PIN o[65]
    DIRECTION OUTPUT ;
    USE SIGNAL ;
    PORT
      LAYER M5 ;
        RECT  8.688 21.516 8.712 21.6 ;
    END
  END o[65]
  PIN o[66]
    DIRECTION OUTPUT ;
    USE SIGNAL ;
    PORT
      LAYER M5 ;
        RECT  8.784 21.516 8.808 21.6 ;
    END
  END o[66]
  PIN o[67]
    DIRECTION OUTPUT ;
    USE SIGNAL ;
    PORT
      LAYER M5 ;
        RECT  8.88 21.516 8.904 21.6 ;
    END
  END o[67]
  PIN o[68]
    DIRECTION OUTPUT ;
    USE SIGNAL ;
    PORT
      LAYER M5 ;
        RECT  8.976 21.516 9 21.6 ;
    END
  END o[68]
  PIN o[69]
    DIRECTION OUTPUT ;
    USE SIGNAL ;
    PORT
      LAYER M5 ;
        RECT  9.072 21.516 9.096 21.6 ;
    END
  END o[69]
  PIN o[6]
    DIRECTION OUTPUT ;
    USE SIGNAL ;
    PORT
      LAYER M5 ;
        RECT  15.312 21.516 15.336 21.6 ;
    END
  END o[6]
  PIN o[70]
    DIRECTION OUTPUT ;
    USE SIGNAL ;
    PORT
      LAYER M5 ;
        RECT  9.168 21.516 9.192 21.6 ;
    END
  END o[70]
  PIN o[71]
    DIRECTION OUTPUT ;
    USE SIGNAL ;
    PORT
      LAYER M5 ;
        RECT  9.264 21.516 9.288 21.6 ;
    END
  END o[71]
  PIN o[72]
    DIRECTION OUTPUT ;
    USE SIGNAL ;
    PORT
      LAYER M5 ;
        RECT  9.36 21.516 9.384 21.6 ;
    END
  END o[72]
  PIN o[73]
    DIRECTION OUTPUT ;
    USE SIGNAL ;
    PORT
      LAYER M5 ;
        RECT  9.456 21.516 9.48 21.6 ;
    END
  END o[73]
  PIN o[74]
    DIRECTION OUTPUT ;
    USE SIGNAL ;
    PORT
      LAYER M5 ;
        RECT  9.552 21.516 9.576 21.6 ;
    END
  END o[74]
  PIN o[75]
    DIRECTION OUTPUT ;
    USE SIGNAL ;
    PORT
      LAYER M5 ;
        RECT  9.648 21.516 9.672 21.6 ;
    END
  END o[75]
  PIN o[76]
    DIRECTION OUTPUT ;
    USE SIGNAL ;
    PORT
      LAYER M5 ;
        RECT  9.744 21.516 9.768 21.6 ;
    END
  END o[76]
  PIN o[77]
    DIRECTION OUTPUT ;
    USE SIGNAL ;
    PORT
      LAYER M5 ;
        RECT  9.84 21.516 9.864 21.6 ;
    END
  END o[77]
  PIN o[78]
    DIRECTION OUTPUT ;
    USE SIGNAL ;
    PORT
      LAYER M5 ;
        RECT  9.936 21.516 9.96 21.6 ;
    END
  END o[78]
  PIN o[79]
    DIRECTION OUTPUT ;
    USE SIGNAL ;
    PORT
      LAYER M5 ;
        RECT  10.032 21.516 10.056 21.6 ;
    END
  END o[79]
  PIN o[7]
    DIRECTION OUTPUT ;
    USE SIGNAL ;
    PORT
      LAYER M5 ;
        RECT  15.408 21.516 15.432 21.6 ;
    END
  END o[7]
  PIN o[80]
    DIRECTION OUTPUT ;
    USE SIGNAL ;
    PORT
      LAYER M5 ;
        RECT  10.128 21.516 10.152 21.6 ;
    END
  END o[80]
  PIN o[81]
    DIRECTION OUTPUT ;
    USE SIGNAL ;
    PORT
      LAYER M5 ;
        RECT  10.224 21.516 10.248 21.6 ;
    END
  END o[81]
  PIN o[82]
    DIRECTION OUTPUT ;
    USE SIGNAL ;
    PORT
      LAYER M5 ;
        RECT  10.32 21.516 10.344 21.6 ;
    END
  END o[82]
  PIN o[83]
    DIRECTION OUTPUT ;
    USE SIGNAL ;
    PORT
      LAYER M5 ;
        RECT  10.416 21.516 10.44 21.6 ;
    END
  END o[83]
  PIN o[84]
    DIRECTION OUTPUT ;
    USE SIGNAL ;
    PORT
      LAYER M5 ;
        RECT  10.512 21.516 10.536 21.6 ;
    END
  END o[84]
  PIN o[85]
    DIRECTION OUTPUT ;
    USE SIGNAL ;
    PORT
      LAYER M5 ;
        RECT  10.608 21.516 10.632 21.6 ;
    END
  END o[85]
  PIN o[86]
    DIRECTION OUTPUT ;
    USE SIGNAL ;
    PORT
      LAYER M5 ;
        RECT  10.704 21.516 10.728 21.6 ;
    END
  END o[86]
  PIN o[87]
    DIRECTION OUTPUT ;
    USE SIGNAL ;
    PORT
      LAYER M5 ;
        RECT  10.8 21.516 10.824 21.6 ;
    END
  END o[87]
  PIN o[88]
    DIRECTION OUTPUT ;
    USE SIGNAL ;
    PORT
      LAYER M5 ;
        RECT  10.896 21.516 10.92 21.6 ;
    END
  END o[88]
  PIN o[89]
    DIRECTION OUTPUT ;
    USE SIGNAL ;
    PORT
      LAYER M5 ;
        RECT  10.992 21.516 11.016 21.6 ;
    END
  END o[89]
  PIN o[8]
    DIRECTION OUTPUT ;
    USE SIGNAL ;
    PORT
      LAYER M5 ;
        RECT  15.504 21.516 15.528 21.6 ;
    END
  END o[8]
  PIN o[90]
    DIRECTION OUTPUT ;
    USE SIGNAL ;
    PORT
      LAYER M5 ;
        RECT  11.088 21.516 11.112 21.6 ;
    END
  END o[90]
  PIN o[91]
    DIRECTION OUTPUT ;
    USE SIGNAL ;
    PORT
      LAYER M5 ;
        RECT  11.184 21.516 11.208 21.6 ;
    END
  END o[91]
  PIN o[92]
    DIRECTION OUTPUT ;
    USE SIGNAL ;
    PORT
      LAYER M5 ;
        RECT  11.28 21.516 11.304 21.6 ;
    END
  END o[92]
  PIN o[93]
    DIRECTION OUTPUT ;
    USE SIGNAL ;
    PORT
      LAYER M5 ;
        RECT  11.376 21.516 11.4 21.6 ;
    END
  END o[93]
  PIN o[94]
    DIRECTION OUTPUT ;
    USE SIGNAL ;
    PORT
      LAYER M5 ;
        RECT  11.472 21.516 11.496 21.6 ;
    END
  END o[94]
  PIN o[95]
    DIRECTION OUTPUT ;
    USE SIGNAL ;
    PORT
      LAYER M5 ;
        RECT  11.568 21.516 11.592 21.6 ;
    END
  END o[95]
  PIN o[96]
    DIRECTION OUTPUT ;
    USE SIGNAL ;
    PORT
      LAYER M5 ;
        RECT  5.52 21.516 5.544 21.6 ;
    END
  END o[96]
  PIN o[97]
    DIRECTION OUTPUT ;
    USE SIGNAL ;
    PORT
      LAYER M5 ;
        RECT  5.616 21.516 5.64 21.6 ;
    END
  END o[97]
  PIN o[98]
    DIRECTION OUTPUT ;
    USE SIGNAL ;
    PORT
      LAYER M5 ;
        RECT  5.712 21.516 5.736 21.6 ;
    END
  END o[98]
  PIN o[99]
    DIRECTION OUTPUT ;
    USE SIGNAL ;
    PORT
      LAYER M5 ;
        RECT  5.808 21.516 5.832 21.6 ;
    END
  END o[99]
  PIN o[9]
    DIRECTION OUTPUT ;
    USE SIGNAL ;
    PORT
      LAYER M5 ;
        RECT  15.6 21.516 15.624 21.6 ;
    END
  END o[9]
  PIN rs
    DIRECTION INPUT ;
    USE SIGNAL ;
    PORT
      LAYER M4 ;
        RECT  0 9.456 0.084 9.48 ;
    END
  END rs
  PIN rso
    DIRECTION OUTPUT ;
    USE SIGNAL ;
    PORT
      LAYER M5 ;
        RECT  5.424 21.516 5.448 21.6 ;
    END
  END rso
  PIN VDD
    DIRECTION INOUT ;
    USE POWER ;
    PORT
      LAYER M5 ;
        RECT  18.792 2.151 18.912 19.449 ;
        RECT  16.092 2.151 16.212 19.449 ;
        RECT  13.392 2.151 13.512 19.449 ;
        RECT  10.692 2.151 10.812 19.449 ;
        RECT  7.992 2.151 8.112 19.449 ;
        RECT  5.292 2.151 5.412 19.449 ;
        RECT  2.592 2.151 2.712 19.449 ;
    END
  END VDD
  PIN VSS
    DIRECTION INOUT ;
    USE GROUND ;
    PORT
      LAYER M5 ;
        RECT  18.6 2.137 18.72 19.463 ;
        RECT  15.9 2.137 16.02 19.463 ;
        RECT  13.2 2.137 13.32 19.463 ;
        RECT  10.5 2.137 10.62 19.463 ;
        RECT  7.8 2.137 7.92 19.463 ;
        RECT  5.1 2.137 5.22 19.463 ;
        RECT  2.4 2.137 2.52 19.463 ;
    END
  END VSS
  OBS
    LAYER RVTN ;
     RECT  2.16 2.16 19.44 2.295 ;
     RECT  2.16 2.565 19.44 2.835 ;
     RECT  2.16 3.105 19.44 3.375 ;
     RECT  2.16 3.645 19.44 3.915 ;
     RECT  2.16 4.185 19.44 4.455 ;
     RECT  2.16 4.725 19.44 4.995 ;
     RECT  2.16 5.265 19.44 5.535 ;
     RECT  2.16 5.805 19.44 6.075 ;
     RECT  2.16 6.345 19.44 6.615 ;
     RECT  2.16 6.885 19.44 7.155 ;
     RECT  2.16 7.425 19.44 7.695 ;
     RECT  2.16 7.965 19.44 8.235 ;
     RECT  2.16 8.505 19.44 8.775 ;
     RECT  2.16 9.045 19.44 9.315 ;
     RECT  2.16 9.585 19.44 9.855 ;
     RECT  2.16 10.125 19.44 10.395 ;
     RECT  2.16 10.665 19.44 10.935 ;
     RECT  2.16 11.205 19.44 11.475 ;
     RECT  2.16 11.745 19.44 12.015 ;
     RECT  2.16 12.285 19.44 12.555 ;
     RECT  2.16 12.825 19.44 13.095 ;
     RECT  2.16 13.365 19.44 13.635 ;
     RECT  2.16 13.905 19.44 14.175 ;
     RECT  2.16 14.445 19.44 14.715 ;
     RECT  2.16 14.985 19.44 15.255 ;
     RECT  2.16 15.525 19.44 15.795 ;
     RECT  2.16 16.065 19.44 16.335 ;
     RECT  2.16 16.605 19.44 16.875 ;
     RECT  2.16 17.145 19.44 17.415 ;
     RECT  2.16 17.685 19.44 17.955 ;
     RECT  2.16 18.225 19.44 18.495 ;
     RECT  2.16 18.765 19.44 19.035 ;
     RECT  2.16 19.305 19.44 19.44 ;
    LAYER RVTP ;
     RECT  2.16 2.295 19.44 2.565 ;
     RECT  2.16 2.835 19.44 3.105 ;
     RECT  2.16 3.375 19.44 3.645 ;
     RECT  2.16 3.915 19.44 4.185 ;
     RECT  2.16 4.455 19.44 4.725 ;
     RECT  2.16 4.995 19.44 5.265 ;
     RECT  2.16 5.535 19.44 5.805 ;
     RECT  2.16 6.075 19.44 6.345 ;
     RECT  2.16 6.615 19.44 6.885 ;
     RECT  2.16 7.155 19.44 7.425 ;
     RECT  2.16 7.695 19.44 7.965 ;
     RECT  2.16 8.235 19.44 8.505 ;
     RECT  2.16 8.775 19.44 9.045 ;
     RECT  2.16 9.315 19.44 9.585 ;
     RECT  2.16 9.855 19.44 10.125 ;
     RECT  2.16 10.395 19.44 10.665 ;
     RECT  2.16 10.935 19.44 11.205 ;
     RECT  2.16 11.475 19.44 11.745 ;
     RECT  2.16 12.015 19.44 12.285 ;
     RECT  2.16 12.555 19.44 12.825 ;
     RECT  2.16 13.095 19.44 13.365 ;
     RECT  2.16 13.635 19.44 13.905 ;
     RECT  2.16 14.175 19.44 14.445 ;
     RECT  2.16 14.715 19.44 14.985 ;
     RECT  2.16 15.255 19.44 15.525 ;
     RECT  2.16 15.795 19.44 16.065 ;
     RECT  2.16 16.335 19.44 16.605 ;
     RECT  2.16 16.875 19.44 17.145 ;
     RECT  2.16 17.415 19.44 17.685 ;
     RECT  2.16 17.955 19.44 18.225 ;
     RECT  2.16 18.495 19.44 18.765 ;
     RECT  2.16 19.035 19.44 19.305 ;
    LAYER M1 ;
     RECT  2.16 2.151 19.44 19.449 ;
    LAYER M2 ;
     RECT  2.16 2.151 5.971 19.449 ;
     RECT  6.583 1.152 6.683 1.17 ;
     RECT  5.971 2.106 7.979 19.449 ;
     RECT  7.979 2.151 8.851 19.449 ;
     RECT  8.851 2.106 10.391 19.449 ;
     RECT  10.391 2.151 14.323 19.449 ;
     RECT  14.323 2.106 14.711 19.449 ;
     RECT  14.711 2.151 16.663 19.449 ;
     RECT  16.663 2.106 18.563 19.449 ;
     RECT  18.563 2.151 19.44 19.449 ;
     RECT  19.44 10.638 19.499 11.394 ;
     RECT  19.44 17.964 19.535 19.332 ;
     RECT  19.44 9.63 19.571 9.648 ;
     RECT  19.499 10.638 19.967 11.304 ;
     RECT  19.535 17.964 19.967 18.594 ;
     RECT  19.967 11.286 20.003 11.304 ;
     RECT  19.967 18.576 20.003 18.594 ;
     RECT  19.44 14.076 20.039 14.094 ;
    LAYER M3 ;
     RECT  18.828 0.091 18.846 0.221 ;
     RECT  13.608 0.235 13.626 0.461 ;
     RECT  8.388 0.091 8.406 0.523 ;
     RECT  3.96 0.091 3.978 0.571 ;
     RECT  6.156 0.523 6.174 0.571 ;
     RECT  6.156 0.571 6.678 0.619 ;
     RECT  15.48 0.523 15.498 1.099 ;
     RECT  18.036 1.627 18.054 1.675 ;
     RECT  3.96 0.571 4.122 1.723 ;
     RECT  6.156 0.619 7.074 1.723 ;
     RECT  8.136 0.523 8.406 1.723 ;
     RECT  15.48 1.099 15.858 1.723 ;
     RECT  17.676 1.675 18.054 1.723 ;
     RECT  3.42 1.723 4.302 1.771 ;
     RECT  11.268 1.723 11.718 1.771 ;
     RECT  12.708 1.723 13.158 1.915 ;
     RECT  6.156 1.723 10.242 2.011 ;
     RECT  11.124 1.771 11.718 2.011 ;
     RECT  12.708 1.915 13.194 2.011 ;
     RECT  14.004 1.723 19.062 2.011 ;
     RECT  6.156 2.011 11.718 2.101 ;
     RECT  3.42 1.771 4.554 2.143 ;
     RECT  5.976 2.101 11.718 2.191 ;
     RECT  12.708 2.011 19.062 2.191 ;
     RECT  3.42 2.143 5.205 2.227 ;
     RECT  5.976 2.191 19.062 2.227 ;
     RECT  3.42 2.227 19.062 2.255 ;
     RECT  3.528 2.255 19.062 2.263 ;
     RECT  2.415 2.143 2.505 2.413 ;
     RECT  3.528 2.263 19.206 2.489 ;
     RECT  3.708 2.489 19.206 3.271 ;
     RECT  2.415 2.413 2.697 3.379 ;
     RECT  3.708 3.271 19.242 3.379 ;
     RECT  2.415 3.379 19.242 4.181 ;
     RECT  3.996 4.181 19.242 4.379 ;
     RECT  3.996 4.379 19.206 4.757 ;
     RECT  2.415 4.181 2.97 5.099 ;
     RECT  4.068 4.757 19.206 5.225 ;
     RECT  4.068 5.225 19.134 6.539 ;
     RECT  4.248 6.539 19.134 6.809 ;
     RECT  4.248 6.809 4.338 7.321 ;
     RECT  3.636 7.321 4.338 7.933 ;
     RECT  5.115 6.809 19.134 7.933 ;
     RECT  3.636 7.933 19.134 8.041 ;
     RECT  3.636 8.041 19.314 8.539 ;
     RECT  2.415 5.099 2.697 9.451 ;
     RECT  3.636 8.539 19.458 9.581 ;
     RECT  9.684 9.581 19.458 9.625 ;
     RECT  9.684 9.625 19.566 9.689 ;
     RECT  2.304 9.451 2.697 9.815 ;
     RECT  9.72 9.689 19.566 10.633 ;
     RECT  3.636 9.581 8.838 11.011 ;
     RECT  9.72 10.633 19.962 11.011 ;
     RECT  3.636 11.011 19.962 11.281 ;
     RECT  3.636 11.281 19.998 14.071 ;
     RECT  2.415 9.815 2.697 19.111 ;
     RECT  3.636 14.071 20.034 19.111 ;
     RECT  2.415 19.111 20.034 19.187 ;
     RECT  3.384 19.187 20.034 19.229 ;
     RECT  3.384 19.229 8.766 19.265 ;
     RECT  3.96 19.265 8.766 19.301 ;
     RECT  14.364 19.229 16.506 19.301 ;
     RECT  9.828 19.229 13.305 19.325 ;
     RECT  4.104 19.301 7.905 19.337 ;
     RECT  17.532 19.229 20.034 19.337 ;
     RECT  4.176 19.337 7.905 19.373 ;
     RECT  10.26 19.325 13.305 19.373 ;
     RECT  15.768 19.301 16.506 19.373 ;
     RECT  17.532 19.337 19.062 19.373 ;
     RECT  10.332 19.373 13.305 19.421 ;
     RECT  14.364 19.301 15.03 19.421 ;
     RECT  2.415 19.187 2.505 19.457 ;
     RECT  7.815 19.373 7.905 19.457 ;
     RECT  13.215 19.421 13.305 19.457 ;
     RECT  17.532 19.373 19.026 19.457 ;
     RECT  15.768 19.373 16.362 19.469 ;
     RECT  10.332 19.421 12.15 19.565 ;
     RECT  6.768 19.373 6.822 19.949 ;
     RECT  4.176 19.373 5.922 19.997 ;
     RECT  4.176 19.997 4.626 20.045 ;
     RECT  5.508 19.997 5.922 20.525 ;
     RECT  10.44 19.565 10.458 20.525 ;
     RECT  11.232 19.565 12.15 20.525 ;
     RECT  19.008 19.457 19.026 20.525 ;
     RECT  4.608 20.045 4.626 20.573 ;
     RECT  8.748 19.301 8.766 20.573 ;
     RECT  12.132 20.525 12.15 20.573 ;
     RECT  13.104 21.163 13.122 21.259 ;
     RECT  13.104 21.259 13.626 21.355 ;
     RECT  14.364 19.421 14.382 21.355 ;
     RECT  13.104 21.355 14.382 21.437 ;
     RECT  17.532 19.457 18.27 21.437 ;
     RECT  20.016 19.337 20.034 21.437 ;
     RECT  12.168 21.355 12.186 21.451 ;
     RECT  6.804 19.949 6.822 21.485 ;
     RECT  13.104 21.437 13.914 21.485 ;
     RECT  15.768 19.469 15.786 21.485 ;
     RECT  16.524 21.355 16.542 21.485 ;
     RECT  18.252 21.437 18.27 21.485 ;
     RECT  11.664 21.451 12.186 21.533 ;
     RECT  11.664 21.533 12.006 21.581 ;
    LAYER M4 ;
     RECT  0.06 9.36 2.408 9.48 ;
     RECT  2.408 2.148 2.512 19.452 ;
     RECT  2.512 2.148 2.704 19.182 ;
     RECT  3.409 1.728 3.697 1.752 ;
     RECT  3.877 19.056 3.949 19.08 ;
     RECT  3.949 0.096 4.033 0.12 ;
     RECT  3.949 19.008 4.165 19.08 ;
     RECT  4.093 0.576 4.211 0.6 ;
     RECT  4.165 19.008 4.309 20.04 ;
     RECT  3.697 1.728 4.313 1.8 ;
     RECT  4.309 18.288 4.381 20.04 ;
     RECT  4.381 18.24 4.417 20.04 ;
     RECT  4.313 1.776 4.445 1.8 ;
     RECT  4.309 4.896 4.453 4.92 ;
     RECT  4.405 6.192 4.501 6.216 ;
     RECT  4.417 18.144 4.561 20.04 ;
     RECT  4.445 1.776 4.565 1.896 ;
     RECT  4.561 17.616 4.597 20.04 ;
     RECT  4.501 6.192 4.789 6.6 ;
     RECT  4.597 17.616 4.883 20.568 ;
     RECT  4.417 3.552 4.921 3.576 ;
     RECT  4.921 3.408 5.065 3.576 ;
     RECT  4.453 4.896 5.065 5.064 ;
     RECT  5.065 3.408 5.101 5.064 ;
     RECT  4.789 6.192 5.101 7.416 ;
     RECT  5.101 3.408 5.108 7.416 ;
     RECT  2.704 9.36 5.108 9.384 ;
     RECT  4.741 14.736 5.108 14.76 ;
     RECT  4.7 15.744 5.108 15.768 ;
     RECT  4.883 17.616 5.108 20.52 ;
     RECT  5.108 2.148 5.212 20.52 ;
     RECT  5.212 2.418 5.404 20.52 ;
     RECT  5.404 16.416 5.933 20.52 ;
     RECT  6.277 21.216 6.373 21.24 ;
     RECT  5.404 3.12 6.397 3.48 ;
     RECT  5.933 16.416 6.421 20.232 ;
     RECT  5.404 10.8 6.428 10.824 ;
     RECT  6.421 16.32 6.469 20.232 ;
     RECT  5.404 8.976 6.565 9.384 ;
     RECT  6.397 3.024 6.577 3.48 ;
     RECT  5.404 4.464 6.577 7.992 ;
     RECT  5.404 14.304 6.613 14.76 ;
     RECT  6.469 15.84 6.613 20.232 ;
     RECT  6.428 10.704 6.617 10.824 ;
     RECT  6.145 0.528 6.649 0.552 ;
     RECT  6.565 8.976 6.677 9.672 ;
     RECT  6.617 10.704 6.677 10.728 ;
     RECT  6.373 21.216 6.749 21.336 ;
     RECT  6.677 8.976 6.761 10.728 ;
     RECT  6.613 14.304 6.764 20.232 ;
     RECT  6.764 14.256 6.833 20.232 ;
     RECT  6.649 0.528 7.045 0.6 ;
     RECT  6.833 15.744 7.093 20.232 ;
     RECT  6.749 21.216 7.093 21.48 ;
     RECT  7.045 0.528 7.129 0.648 ;
     RECT  7.129 0.528 7.283 0.6 ;
     RECT  7.093 15.744 7.381 21.48 ;
     RECT  6.577 3.024 7.441 7.992 ;
     RECT  7.283 0.528 7.573 0.552 ;
     RECT  7.573 0.192 7.669 0.552 ;
     RECT  6.937 1.728 7.808 1.752 ;
     RECT  7.441 2.88 7.808 7.992 ;
     RECT  6.761 8.976 7.808 9.672 ;
     RECT  6.761 10.704 7.808 10.728 ;
     RECT  6.833 14.256 7.808 14.28 ;
     RECT  7.381 15.744 7.808 21.576 ;
     RECT  7.808 1.728 8.104 21.576 ;
     RECT  7.669 0.144 8.188 0.552 ;
     RECT  8.104 15.648 8.561 21.576 ;
     RECT  8.561 15.84 8.867 21.576 ;
     RECT  8.377 0.096 9.011 0.12 ;
     RECT  8.104 1.728 9.452 1.848 ;
     RECT  8.104 2.88 9.452 9.384 ;
     RECT  9.452 1.728 9.457 9.384 ;
     RECT  9.457 1.728 9.539 9.48 ;
     RECT  9.539 2.88 9.673 9.48 ;
     RECT  8.867 15.84 9.973 20.52 ;
     RECT  8.867 21.552 9.973 21.576 ;
     RECT  10.069 14.208 10.117 14.232 ;
     RECT  9.973 15.84 10.117 21.576 ;
     RECT  9.673 2.88 10.133 9.672 ;
     RECT  10.261 0.192 10.357 0.216 ;
     RECT  10.133 2.88 10.357 10.248 ;
     RECT  9.539 1.728 10.508 1.848 ;
     RECT  10.357 2.88 10.508 10.92 ;
     RECT  10.117 13.68 10.508 14.232 ;
     RECT  10.117 15.36 10.508 21.576 ;
     RECT  10.357 0.144 10.547 0.216 ;
     RECT  10.547 0.192 10.643 0.216 ;
     RECT  10.508 1.728 10.643 21.576 ;
     RECT  10.643 1.728 10.804 20.52 ;
     RECT  10.804 1.728 10.901 10.872 ;
     RECT  10.901 2.88 10.973 10.872 ;
     RECT  10.804 14.208 11.161 20.52 ;
     RECT  10.901 1.728 11.225 1.848 ;
     RECT  11.225 1.728 11.369 1.8 ;
     RECT  11.161 14.544 11.405 20.52 ;
     RECT  10.973 10.272 11.411 10.872 ;
     RECT  11.405 15.312 11.513 20.52 ;
     RECT  11.513 15.36 11.653 20.52 ;
     RECT  10.643 21.552 11.653 21.576 ;
     RECT  10.804 11.952 11.809 11.976 ;
     RECT  10.973 2.88 12.121 9.288 ;
     RECT  11.411 10.272 12.121 10.824 ;
     RECT  11.653 15.36 12.275 21.576 ;
     RECT  12.121 2.88 12.733 10.824 ;
     RECT  11.369 1.728 12.901 1.752 ;
     RECT  12.733 2.832 12.901 10.824 ;
     RECT  12.901 1.728 13.208 10.824 ;
     RECT  12.325 13.056 13.208 13.08 ;
     RECT  12.229 14.208 13.208 14.232 ;
     RECT  12.275 15.36 13.208 19.656 ;
     RECT  13.208 1.728 13.504 19.656 ;
     RECT  13.477 0.336 13.573 0.36 ;
     RECT  13.573 0.24 13.597 0.36 ;
     RECT  13.597 0.24 13.66 0.456 ;
     RECT  13.66 0.432 13.681 0.456 ;
     RECT  13.504 13.344 14.141 19.656 ;
     RECT  14.141 13.344 14.705 14.28 ;
     RECT  13.504 1.728 14.789 11.16 ;
     RECT  14.705 12.528 14.789 14.28 ;
     RECT  14.789 1.728 14.861 1.848 ;
     RECT  14.789 2.88 14.897 11.16 ;
     RECT  14.141 15.36 15.205 19.656 ;
     RECT  12.275 21.024 15.205 21.576 ;
     RECT  15.205 15.36 15.491 21.576 ;
     RECT  15.452 0.528 15.733 0.552 ;
     RECT  14.789 13.344 15.74 14.28 ;
     RECT  15.491 15.36 15.74 19.656 ;
     RECT  14.861 1.728 15.793 1.8 ;
     RECT  15.733 0.144 15.829 0.552 ;
     RECT  15.793 1.68 15.829 1.8 ;
     RECT  15.829 0.144 15.908 1.8 ;
     RECT  14.897 3.12 15.908 11.16 ;
     RECT  15.74 13.344 15.908 19.656 ;
     RECT  15.908 0.144 16.204 19.656 ;
     RECT  16.204 0.144 16.211 11.688 ;
     RECT  16.211 1.728 16.451 11.688 ;
     RECT  16.211 0.144 16.499 0.552 ;
     RECT  16.499 0.432 16.547 0.456 ;
     RECT  16.451 2.88 16.739 11.688 ;
     RECT  16.204 13.056 16.877 13.368 ;
     RECT  16.451 1.728 16.913 1.848 ;
     RECT  16.739 2.88 16.949 11.4 ;
     RECT  16.204 15.792 17.125 19.656 ;
     RECT  15.491 21.024 17.125 21.576 ;
     RECT  17.125 15.792 17.171 21.576 ;
     RECT  16.949 2.88 17.309 11.16 ;
     RECT  17.171 20.448 17.561 21.576 ;
     RECT  16.877 13.104 17.603 13.368 ;
     RECT  16.913 1.728 17.632 1.8 ;
     RECT  17.171 15.792 17.665 19.368 ;
     RECT  17.632 1.68 18.025 1.8 ;
     RECT  17.561 20.496 18.323 21.576 ;
     RECT  17.309 2.88 18.349 9.096 ;
     RECT  17.309 10.224 18.349 11.16 ;
     RECT  18.323 20.496 18.419 21.528 ;
     RECT  18.025 1.632 18.428 1.8 ;
     RECT  18.349 2.88 18.428 11.16 ;
     RECT  18.428 1.632 18.608 11.16 ;
     RECT  17.603 13.344 18.608 13.368 ;
     RECT  17.665 15.072 18.608 19.368 ;
     RECT  18.608 1.632 18.707 19.452 ;
     RECT  18.707 1.728 18.712 19.452 ;
     RECT  18.421 0.144 18.802 0.168 ;
     RECT  18.712 1.728 18.904 19.368 ;
     RECT  18.904 3.936 18.965 5.544 ;
     RECT  18.802 0.096 18.995 0.216 ;
     RECT  18.904 2.88 19.001 2.904 ;
     RECT  18.419 20.496 19.037 21.432 ;
     RECT  18.995 0.192 19.043 0.216 ;
     RECT  18.965 4.704 19.043 5.544 ;
     RECT  18.904 7.728 19.043 9.288 ;
     RECT  18.904 1.728 19.073 1.752 ;
     RECT  18.904 17.376 19.073 19.368 ;
     RECT  19.043 4.944 19.091 5.544 ;
     RECT  18.904 10.32 19.091 11.16 ;
     RECT  19.073 17.376 19.091 19.272 ;
     RECT  19.043 7.728 19.145 8.808 ;
     RECT  19.091 5.52 19.427 5.544 ;
     RECT  19.145 8.208 19.475 8.808 ;
     RECT  19.091 17.904 19.475 19.272 ;
     RECT  19.475 8.784 19.523 8.808 ;
     RECT  19.475 17.904 19.523 19.032 ;
     RECT  19.523 18.96 19.577 19.032 ;
     RECT  19.091 10.608 20.003 11.16 ;
     RECT  19.577 18.96 20.003 18.984 ;
     RECT  19.037 21.408 20.045 21.432 ;
     RECT  20.003 10.608 20.051 10.632 ;
     RECT  19.523 17.904 20.051 17.928 ;
    LAYER M5 ;
     RECT  6.864 0.016 19.08 0.563 ;
     RECT  3.792 0.016 4.488 1.763 ;
     RECT  6.96 0.563 19.08 1.763 ;
     RECT  3.888 1.763 4.488 1.811 ;
     RECT  4.464 1.811 4.488 1.907 ;
     RECT  2.4 2.137 2.52 2.151 ;
     RECT  5.1 2.137 5.22 2.151 ;
     RECT  5.1 2.151 5.412 3.397 ;
     RECT  7.152 1.763 19.08 4.067 ;
     RECT  10.5 4.067 19.08 4.547 ;
     RECT  18 4.547 19.08 4.691 ;
     RECT  5.1 3.397 5.544 5.029 ;
     RECT  7.152 4.067 9.288 5.077 ;
     RECT  10.5 4.547 16.488 5.077 ;
     RECT  5.1 5.029 5.688 5.125 ;
     RECT  7.152 5.077 16.488 5.125 ;
     RECT  5.1 5.125 16.488 5.171 ;
     RECT  12.624 5.171 16.488 5.315 ;
     RECT  12.672 5.315 16.488 5.411 ;
     RECT  18.144 4.691 19.08 5.509 ;
     RECT  5.1 5.171 11.304 6.181 ;
     RECT  12.912 5.411 16.44 6.275 ;
     RECT  18.144 5.509 19.416 6.565 ;
     RECT  4.416 6.181 11.304 6.659 ;
     RECT  12.912 6.275 14.856 6.661 ;
     RECT  4.416 6.659 8.568 6.851 ;
     RECT  15.9 6.275 16.44 7.765 ;
     RECT  9.648 6.659 11.304 7.957 ;
     RECT  12.336 6.661 14.856 7.957 ;
     RECT  7.584 6.851 8.568 8.003 ;
     RECT  9.648 7.957 14.856 8.003 ;
     RECT  18 6.565 19.416 8.197 ;
     RECT  7.8 8.003 8.568 8.485 ;
     RECT  18 8.197 19.464 8.773 ;
     RECT  15.9 7.765 17.016 8.965 ;
     RECT  18 8.773 19.512 8.965 ;
     RECT  4.416 6.851 6.552 9.061 ;
     RECT  7.8 8.485 8.952 9.061 ;
     RECT  15.9 8.965 19.512 9.155 ;
     RECT  15.9 9.155 16.344 9.731 ;
     RECT  10.128 8.003 14.856 9.925 ;
     RECT  15.9 9.731 16.212 9.925 ;
     RECT  18 9.155 19.512 10.213 ;
     RECT  17.952 10.213 19.512 10.597 ;
     RECT  17.952 10.597 20.04 10.741 ;
     RECT  10.128 9.925 16.212 11.365 ;
     RECT  17.472 10.741 20.04 11.365 ;
     RECT  10.128 11.365 20.04 14.197 ;
     RECT  4.416 9.061 8.952 15.973 ;
     RECT  10.08 14.197 20.04 15.973 ;
     RECT  4.416 15.973 20.04 17.939 ;
     RECT  4.416 17.939 19.992 18.275 ;
     RECT  4.512 18.275 19.992 18.995 ;
     RECT  4.656 18.995 19.464 19.283 ;
     RECT  2.4 2.151 2.712 19.449 ;
     RECT  4.656 19.283 18.912 19.449 ;
     RECT  2.4 19.449 2.52 19.463 ;
     RECT  4.656 19.449 18.72 19.463 ;
     RECT  4.656 19.463 18.456 21.395 ;
     RECT  4.656 21.395 18.408 21.539 ;
     RECT  4.656 21.539 18.312 21.584 ;
     RECT  7.392 21.584 7.416 21.587 ;
     RECT  18.288 21.584 18.312 21.587 ;
  END
END hbfd_rly_136_SN_rr
END LIBRARY
